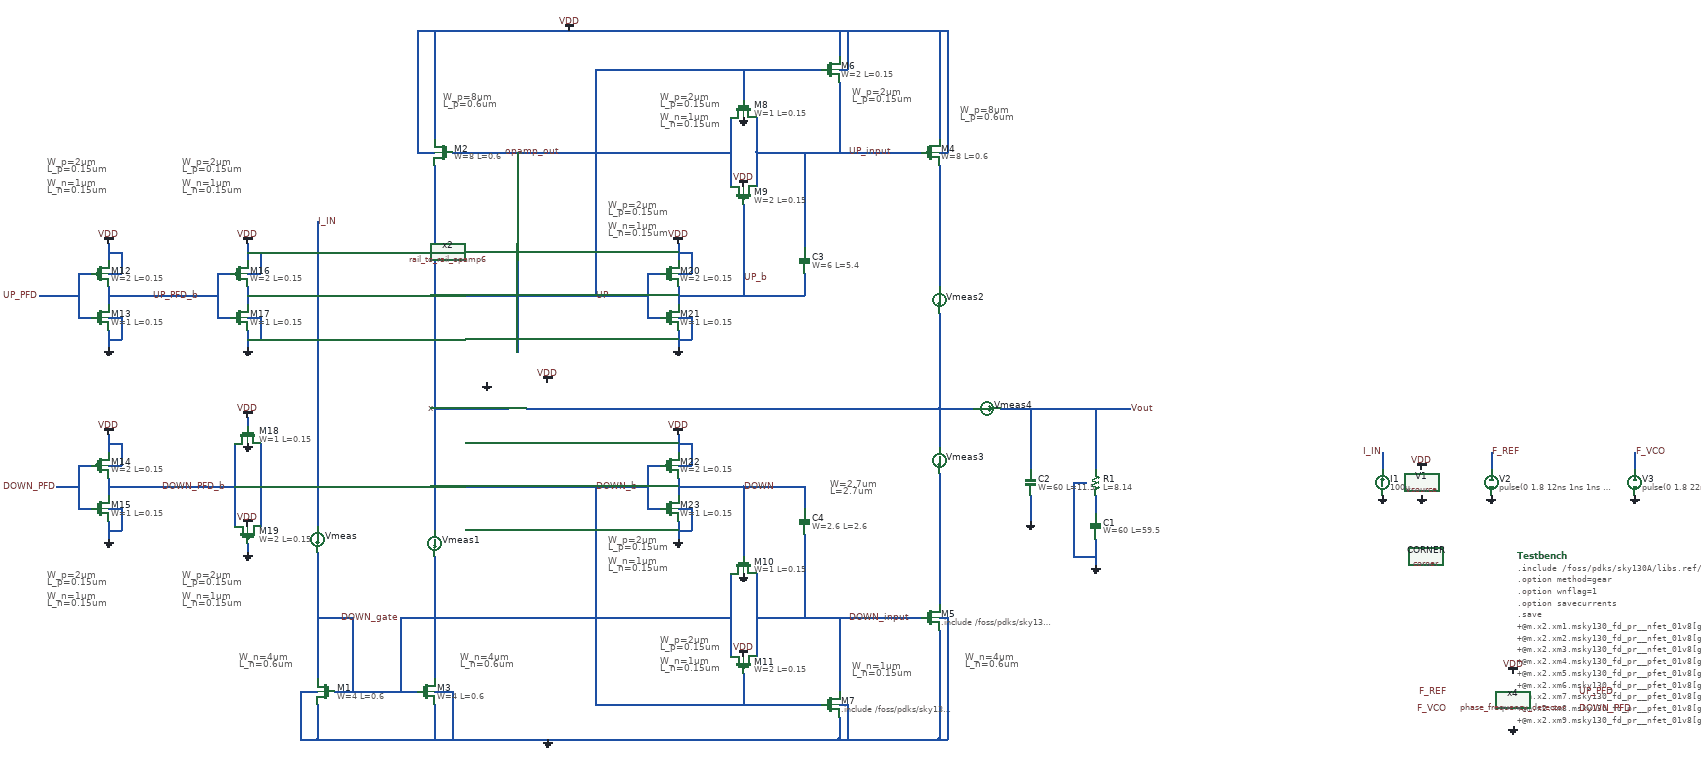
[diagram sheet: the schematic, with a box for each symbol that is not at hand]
v {xschem version=3.4.5 file_version=1.2
}
G {}
K {}
V {}
S {}
E {}
B 2 1320 -2590 2360 -2110 {flags=graph
y1=-0.00011
y2=0.00015
ypos1=0
ypos2=2
divy=5
subdivy=1
unity=1
x1=0
x2=5e-07
divx=5
subdivx=1
xlabmag=1.0
ylabmag=1.0


dataset=0
unitx=1
logx=0
logy=0








linewidth_mult=4
color=6
node="\\"i(@m.xm4.msky130_fd_pr__pfet_01v8[id]) i(@m.xm5.msky130_fd_pr__nfet_01v8[id]) - \\""}
B 2 4200 -3800 5560 -3140 {flags=graph
y1=0
y2=1.8
ypos1=0
ypos2=2
divy=5
subdivy=1
unity=1
x1=0
x2=5e-07
divx=5
subdivx=1
xlabmag=1.0
ylabmag=1.0


dataset=0
unitx=1
logx=0
logy=0








linewidth_mult=3







autoload=0
sim_type=tran
color="6 7"
node="f_ref
f_vco"}
B 2 4200 -2410 5580 -1730 {flags=graph
y1=-0.02
y2=1.9
ypos1=0
ypos2=2
divy=5
subdivy=1
unity=1
x1=0
x2=5e-07
divx=5
subdivx=1
xlabmag=1.0
ylabmag=1.0


dataset=0
unitx=1
logx=0
logy=0








linewidth_mult=5





color="6 5"
node="up_pfd_b
down_pfd_b"}
B 2 4200 -3120 5580 -2420 {flags=graph
y1=-0.038
y2=1.9
ypos1=0
ypos2=2
divy=5
subdivy=1
unity=1
x1=0
x2=5e-07
divx=5
subdivx=1
xlabmag=1.0
ylabmag=1.0


dataset=0
unitx=1
logx=0
logy=0








linewidth_mult=5

color="6 5"
node="up_pfd
down_pfd"}
B 2 2440 -1870 3800 -1200 {flags=graph
y1=0.12
y2=1.8
ypos1=0
ypos2=2
divy=5
subdivy=1
unity=1
x1=0
x2=5e-07
divx=5
subdivx=1
xlabmag=1.0
ylabmag=1.0


dataset=0
unitx=1
logx=0
logy=0








linewidth_mult=4



color="19 7 6"
node="vout
x
opamp_out"}
B 2 420 -3110 1180 -2770 {flags=graph
y1=-0.12
y2=1.9
ypos1=0
ypos2=2
divy=5
subdivy=1
unity=1
x1=0
x2=5e-07
divx=5
subdivx=1
xlabmag=1.0
ylabmag=1.0


dataset=0
unitx=1
logx=0
logy=0








linewidth_mult=3



color="18 6 11 5 12 17"
node="opamp_out
up_input


down_gate
down_input


x


vout"}
B 2 1320 -3100 2360 -2610 {flags=graph
y1=-0.00012
y2=0.00029
ypos1=0
ypos2=2
divy=5
subdivy=1
unity=1
x1=0
x2=5e-07
divx=5
subdivx=1
xlabmag=1.0
ylabmag=1.0


dataset=0
unitx=1
logx=0
logy=0








linewidth_mult=4




color="6 7"
node="i(vmeas2)
i(vmeas3)"}
B 2 4200 -1710 5580 -1030 {flags=graph
y1=-0.013
y2=1.9
ypos1=0
ypos2=2
divy=5
subdivy=1
unity=1
x1=0
x2=5e-07
divx=5
subdivx=1
xlabmag=1.0
ylabmag=1.0


dataset=0
unitx=1
logx=0
logy=0








linewidth_mult=5





color="6 5"
node="up
down_b"}
B 2 4200 -1010 5580 -330 {flags=graph
y1=-0.04
y2=1.9
ypos1=0
ypos2=2
divy=5
subdivy=1
unity=1
x1=0
x2=5e-07
divx=5
subdivx=1
xlabmag=1.0
ylabmag=1.0


dataset=0
unitx=1
logx=0
logy=0








linewidth_mult=5





color="6 5"
node="up_b
down"}
B 2 260 -2590 1300 -2110 {flags=graph
y1=-0.00014
y2=0.00018
ypos1=0
ypos2=2
divy=5
subdivy=1
unity=1
x1=0
x2=5e-07
divx=5
subdivx=1
xlabmag=1.0
ylabmag=1.0


dataset=0
unitx=1
logx=0
logy=0








linewidth_mult=4

color="6 7 18"
node="i(vmeas1)
i(vmeas2)
i(vmeas4)"}
B 2 2440 -2570 3800 -1900 {flags=graph
y1=0.89
y2=1.8
ypos1=0
ypos2=2
divy=5
subdivy=1
unity=1
x1=0
x2=5e-07
divx=5
subdivx=1
xlabmag=1.0
ylabmag=1.0


dataset=0
unitx=1
logx=0
logy=0








linewidth_mult=4



color=6
node=vout}
B 2 2440 -3270 3800 -2600 {flags=graph
y1=8.8
y2=16
ypos1=0
ypos2=2
divy=5
subdivy=1
unity=1
x1=0
x2=5e-07
divx=5
subdivx=1
xlabmag=1.0
ylabmag=1.0


dataset=0
unitx=1
logx=0
logy=0








linewidth_mult=4



color="6 5"
node="\\"@m.x2.xm11.msky130_fd_pr__pfet_01v8[gm] i(@m.x2.xm11.msky130_fd_pr__pfet_01v8[id]) /\\"


\\"@m.x2.xm12.msky130_fd_pr__nfet_01v8[gm] i(@m.x2.xm12.msky130_fd_pr__nfet_01v8[id]) /\\""}
B 2 2440 -3980 3800 -3310 {flags=graph
y1=8.1e-06
y2=1.4e-05
ypos1=0
ypos2=2
divy=5
subdivy=1
unity=1
x1=0
x2=5e-07
divx=5
subdivx=1
xlabmag=1.0
ylabmag=1.0


dataset=0
unitx=1
logx=0
logy=0








linewidth_mult=4





color="6 7"
node="i(@m.x2.xm1.msky130_fd_pr__nfet_01v8[id])
i(@m.x2.xm6.msky130_fd_pr__pfet_01v8[id])"}
B 2 1040 -3980 2400 -3310 {flags=graph
y1=6.4e-05
y2=0.00051
ypos1=0
ypos2=2
divy=5
subdivy=1
unity=1
x1=0
x2=5e-07
divx=5
subdivx=1
xlabmag=1.0
ylabmag=1.0


dataset=0
unitx=1
logx=0
logy=0








linewidth_mult=4



color="6 7"
node="@m.x2.xm11.msky130_fd_pr__pfet_01v8[gm]


@m.x2.xm12.msky130_fd_pr__nfet_01v8[gm]"}
B 2 -380 -3980 980 -3310 {flags=graph
y1=1.3e-05
y2=1.5e-05
ypos1=0
ypos2=2
divy=5
subdivy=1
unity=1
x1=0
x2=5e-07
divx=5
subdivx=1
xlabmag=1.0
ylabmag=1.0


dataset=0
unitx=1
logx=0
logy=0








linewidth_mult=4




color=6
node=i(v.x2.vmeas)}
T {W_p=2um
L_p=0.15um

W_n=1um
L_n=0.15um} 210 -1680 0 0 0.4 0.4 {}
T {W_p=2um
L_p=0.15um

W_n=1um
L_n=0.15um} 210 -730 0 0 0.4 0.4 {}
T {W_p=2um
L_p=0.15um

W_n=1um
L_n=0.15um} 520 -1680 0 0 0.4 0.4 {}
T {W_p=2um
L_p=0.15um

W_n=1um
L_n=0.15um} 520 -730 0 0 0.4 0.4 {}
T {W_p=2um
L_p=0.15um

W_n=1um
L_n=0.15um} 1500 -1580 0 0 0.4 0.4 {}
T {W_p=2um
L_p=0.15um

W_n=1um
L_n=0.15um} 1500 -810 0 0 0.4 0.4 {}
T {W_n=4um
L_n=0.6um} 650 -540 0 0 0.4 0.4 {}
T {W_n=4um
L_n=0.6um} 1160 -540 0 0 0.4 0.4 {}
T {W_p=2um
L_p=0.15um

W_n=1um
L_n=0.15um} 1620 -580 0 0 0.4 0.4 {}
T {W_p=2um
L_p=0.15um

W_n=1um
L_n=0.15um} 1620 -1830 0 0 0.4 0.4 {}
T {W_p=8um
L_p=0.6um} 1120 -1830 0 0 0.4 0.4 {}
T {W_p=8um
L_p=0.6um} 2310 -1800 0 0 0.4 0.4 {}
T {W_n=4um
L_n=0.6um} 2320 -540 0 0 0.4 0.4 {}
T {W_n=1um
L_n=0.15um} 2060 -520 0 0 0.4 0.4 {}
T {W_p=2um
L_p=0.15um} 2060 -1840 0 0 0.4 0.4 {}
T {W=2.7um
L=2.7um} 2010 -940 0 0 0.4 0.4 {}
N 2620 -900 2620 -850 {
lab=#net1}
N 2620 -1100 2620 -960 {
lab=Vout}
N 2620 -800 2620 -740 {
lab=GND}
N 2570 -930 2600 -930 {
lab=GND}
N 2570 -930 2570 -760 {
lab=GND}
N 2570 -760 2620 -760 {
lab=GND}
N 2470 -1100 2470 -960 {
lab=Vout}
N 2470 -900 2470 -840 {
lab=GND}
N 3530 -1000 3530 -960 {
lab=F_REF}
N 3860 -1000 3860 -960 {
lab=F_VCO}
N 2400 -1100 2700 -1100 {
lab=Vout}
N 3280 -1000 3280 -960 {
lab=I_IN}
N 870 -450 1060 -450 {
lab=DOWN_gate}
N 830 -420 830 -340 {
lab=GND}
N 830 -340 1390 -340 {
lab=GND}
N 790 -450 830 -450 {
lab=GND}
N 790 -450 790 -340 {
lab=GND}
N 790 -340 830 -340 {
lab=GND}
N 1100 -450 1140 -450 {
lab=GND}
N 1060 -1690 1100 -1690 {
lab=VDD}
N 1390 -340 1430 -340 {
lab=GND}
N 1100 -1970 1100 -1720 {
lab=VDD}
N 1060 -1970 1060 -1690 {
lab=VDD}
N 2260 -1970 2260 -1720 {
lab=VDD}
N 2030 -1970 2030 -1910 {
lab=VDD}
N 2030 -1880 2050 -1880 {
lab=VDD}
N 2050 -1970 2050 -1880 {
lab=VDD}
N 2280 -1970 2280 -1690 {
lab=VDD}
N 2260 -1690 2280 -1690 {
lab=VDD}
N 2260 -1660 2260 -1380 {
lab=#net2}
N 1430 -340 2030 -340 {
lab=GND}
N 2030 -390 2030 -340 {
lab=GND}
N 2260 -620 2280 -620 {
lab=GND}
N 2260 -340 2280 -340 {
lab=GND}
N 450 -1360 550 -1360 {
lab=UP_PFD_b}
N 490 -920 640 -920 {
lab=DOWN_PFD_b}
N 190 -1360 230 -1360 {
lab=UP_PFD}
N 230 -920 270 -920 {
lab=DOWN_PFD}
N 1100 -1660 1100 -1220 {
lab=x}
N 1100 -1100 1270 -1100 {
lab=x}
N 1310 -1100 2260 -1100 {
lab=#net3}
N 1290 -1690 1290 -1230 {
lab=opamp_out}
N 910 -620 910 -450 {
lab=DOWN_gate}
N 830 -620 910 -620 {
lab=DOWN_gate}
N 1140 -450 1140 -340 {
lab=GND}
N 1100 -420 1100 -340 {
lab=GND}
N 1020 -620 1780 -620 {
lab=DOWN_gate}
N 700 -920 1540 -920 {
lab=DOWN_b}
N 1810 -1570 1810 -1360 {
lab=UP_b}
N 1470 -1880 1990 -1880 {
lab=UP}
N 1470 -1880 1470 -1360 {
lab=UP}
N 2030 -1850 2030 -1690 {
lab=UP_input}
N 1840 -1690 2220 -1690 {
lab=UP_input}
N 1060 -1970 2280 -1970 {
lab=VDD}
N 1750 -920 1810 -920 {
lab=DOWN}
N 1810 -920 1810 -760 {
lab=DOWN}
N 1470 -920 1470 -420 {
lab=DOWN_b}
N 1470 -420 1990 -420 {
lab=DOWN_b}
N 640 -1020 640 -830 {
lab=DOWN_PFD_b}
N 700 -1020 700 -830 {
lab=DOWN_b}
N 670 -1080 670 -1060 {
lab=VDD}
N 670 -790 670 -770 {
lab=GND}
N 350 -940 350 -900 {
lab=DOWN_PFD_b}
N 280 -970 310 -970 {
lab=DOWN_PFD}
N 280 -970 280 -870 {
lab=DOWN_PFD}
N 280 -870 310 -870 {
lab=DOWN_PFD}
N 350 -920 490 -920 {
lab=DOWN_PFD_b}
N 270 -920 280 -920 {
lab=DOWN_PFD}
N 350 -840 350 -800 {
lab=GND}
N 350 -1040 350 -1000 {
lab=VDD}
N 350 -970 380 -970 {
lab=VDD}
N 380 -1020 380 -970 {
lab=VDD}
N 350 -1020 380 -1020 {
lab=VDD}
N 350 -870 380 -870 {
lab=GND}
N 380 -870 380 -820 {
lab=GND}
N 350 -820 380 -820 {
lab=GND}
N 350 -1380 350 -1340 {
lab=UP_PFD_b}
N 280 -1410 310 -1410 {
lab=UP_PFD}
N 280 -1410 280 -1310 {
lab=UP_PFD}
N 280 -1310 310 -1310 {
lab=UP_PFD}
N 350 -1360 450 -1360 {
lab=UP_PFD_b}
N 230 -1360 280 -1360 {
lab=UP_PFD}
N 350 -1280 350 -1240 {
lab=GND}
N 350 -1480 350 -1440 {
lab=VDD}
N 350 -1410 380 -1410 {
lab=VDD}
N 380 -1460 380 -1410 {
lab=VDD}
N 350 -1460 380 -1460 {
lab=VDD}
N 350 -1310 380 -1310 {
lab=GND}
N 380 -1310 380 -1260 {
lab=GND}
N 350 -1260 380 -1260 {
lab=GND}
N 670 -1380 670 -1340 {
lab=UP}
N 600 -1410 630 -1410 {
lab=UP_PFD_b}
N 600 -1410 600 -1310 {
lab=UP_PFD_b}
N 600 -1310 630 -1310 {
lab=UP_PFD_b}
N 550 -1360 600 -1360 {
lab=UP_PFD_b}
N 670 -1280 670 -1240 {
lab=GND}
N 670 -1480 670 -1440 {
lab=VDD}
N 670 -1410 700 -1410 {
lab=VDD}
N 700 -1460 700 -1410 {
lab=VDD}
N 670 -1460 700 -1460 {
lab=VDD}
N 670 -1310 700 -1310 {
lab=GND}
N 700 -1310 700 -1260 {
lab=GND}
N 670 -1260 700 -1260 {
lab=GND}
N 1660 -940 1660 -900 {
lab=DOWN}
N 1590 -970 1620 -970 {
lab=DOWN_b}
N 1590 -970 1590 -870 {
lab=DOWN_b}
N 1590 -870 1620 -870 {
lab=DOWN_b}
N 1540 -920 1590 -920 {
lab=DOWN_b}
N 1660 -840 1660 -800 {
lab=GND}
N 1660 -1040 1660 -1000 {
lab=VDD}
N 1660 -970 1690 -970 {
lab=VDD}
N 1690 -1020 1690 -970 {
lab=VDD}
N 1660 -1020 1690 -1020 {
lab=VDD}
N 1660 -870 1690 -870 {
lab=GND}
N 1690 -870 1690 -820 {
lab=GND}
N 1660 -820 1690 -820 {
lab=GND}
N 1660 -920 1750 -920 {
lab=DOWN}
N 1660 -1380 1660 -1340 {
lab=UP_b}
N 1590 -1410 1620 -1410 {
lab=UP}
N 1590 -1410 1590 -1310 {
lab=UP}
N 1590 -1310 1620 -1310 {
lab=UP}
N 1470 -1360 1590 -1360 {
lab=UP}
N 1660 -1280 1660 -1240 {
lab=GND}
N 1660 -1480 1660 -1440 {
lab=VDD}
N 1660 -1410 1690 -1410 {
lab=VDD}
N 1690 -1460 1690 -1410 {
lab=VDD}
N 1660 -1460 1690 -1460 {
lab=VDD}
N 1660 -1310 1690 -1310 {
lab=GND}
N 1690 -1310 1690 -1260 {
lab=GND}
N 1660 -1260 1690 -1260 {
lab=GND}
N 1660 -1360 1750 -1360 {
lab=UP_b}
N 1750 -1360 1810 -1360 {
lab=UP_b}
N 670 -1360 1470 -1360 {
lab=UP}
N 1100 -1220 1100 -1160 {
lab=x}
N 830 -1530 830 -830 {
lab=I_IN}
N 1100 -1160 1100 -820 {
lab=x}
N 1100 -740 1100 -480 {
lab=#net4}
N 830 -770 830 -760 {
lab=DOWN_gate}
N 830 -660 830 -480 {
lab=DOWN_gate}
N 1100 -760 1100 -740 {
lab=#net4}
N 830 -760 830 -660 {
lab=DOWN_gate}
N 1840 -1770 1840 -1690 {
lab=UP_input}
N 1780 -1770 1780 -1610 {
lab=opamp_out}
N 1840 -1690 1840 -1610 {
lab=UP_input}
N 1140 -1690 1780 -1690 {
lab=opamp_out}
N 2030 -340 2260 -340 {
lab=GND}
N 1840 -720 1840 -530 {
lab=DOWN_input}
N 1780 -720 1780 -530 {
lab=DOWN_gate}
N 1840 -620 2220 -620 {
lab=DOWN_input}
N 2260 -590 2260 -340 {
lab=GND}
N 2280 -620 2280 -340 {
lab=GND}
N 1020 -620 1020 -450 {
lab=DOWN_gate}
N 2030 -620 2030 -450 {
lab=DOWN_input}
N 2030 -420 2050 -420 {
lab=GND}
N 2050 -420 2050 -340 {
lab=GND}
N 1810 -1880 1810 -1810 {
lab=UP}
N 2260 -950 2260 -650 {
lab=#net5}
N 2260 -1100 2260 -1010 {
lab=#net3}
N 2260 -1320 2260 -1100 {
lab=#net3}
N 1810 -1360 1950 -1360 {
lab=UP_b}
N 1950 -1410 1950 -1360 {
lab=UP_b}
N 1950 -1690 1950 -1470 {
lab=UP_input}
N 1950 -920 1950 -870 {
lab=DOWN}
N 1950 -810 1950 -620 {
lab=DOWN_input}
N 1810 -920 1950 -920 {
lab=DOWN}
N 2260 -1100 2340 -1100 {
lab=#net3}
N 1810 -490 1810 -420 {
lab=DOWN_b}
C {sky130_fd_pr/corner.sym} 3380 -760 0 0 {name=CORNER only_toplevel=false corner=tt
value="

.include /foss/pdks/sky130A/libs.ref/sky130_fd_sc_hd/spice/sky130_fd_sc_hd.spice

.option method=gear
.option wnflag=1

* V_out initial voltage value for the F_VCO delay of 2ns  (leading)
* .ic v(vout) = 1.8

* V_out initial voltage value for the F_VCO delay of 12ns (lock condition)
.ic v(vout) = 0.83

* V_out initial voltage value for the F_VCO delay of 22ns (lagging)
* .ic v(vout) = 0

.control
  save v(f_ref) save v(f_vco) save v(i_in) save v(up_pfd) v(down_pfd) v(up_pfd_b) v(down_pfd_b) v(up) v(up_b) v(down) v(down_b) v(x) v(opamp_out) v(up_input) v(down_input) v(down_gate) v(vout)

  * timestep for exact simulation results
  * tran 5ps 0.5us

  * timestep for faster simulation results
  tran 50ps 0.5us

  remzerovec
  write pfd_charge_pump_10.raw
  set appendwrite

.endc

"


v(vout)="0.0

.control
  save all

  * timestep for exact simulation results
  tran 5ps 0.5us

  * timestep for faster simulation results
  * tran 50ps 0.5us

  remzerovec
  write pfd_chargA}
C {devices/code.sym} 3590 -761.25 0 0 {name=Testbench only_toplevel=false value="

.include /foss/pdks/sky130A/libs.ref/sky130_fd_sc_hd/spice/sky130_fd_sc_hd.spice

.option method=gear
.option wnflag=1
.option savecurrents

.save
+@m.x2.xm1.msky130_fd_pr__nfet_01v8[gm]
+@m.x2.xm2.msky130_fd_pr__nfet_01v8[gm]
+@m.x2.xm3.msky130_fd_pr__nfet_01v8[gm]
+@m.x2.xm4.msky130_fd_pr__pfet_01v8[gm]
+@m.x2.xm5.msky130_fd_pr__pfet_01v8[gm]
+@m.x2.xm6.msky130_fd_pr__pfet_01v8[gm]
+@m.x2.xm7.msky130_fd_pr__pfet_01v8[gm]
+@m.x2.xm8.msky130_fd_pr__pfet_01v8[gm]
+@m.x2.xm9.msky130_fd_pr__nfet_01v8[gm]
+@m.x2.xm10.msky130_fd_pr__nfet_01v8[gm]
+@m.x2.xm11.msky130_fd_pr__pfet_01v8[gm]
+@m.x2.xm12.msky130_fd_pr__nfet_01v8[gm]
+@m.x2.xm13.msky130_fd_pr__pfet_01v8[gm]
+@m.x2.xm15.msky130_fd_pr__nfet_01v8[gm]

* V_out initial voltage value for the F_VCO delay of 2ns  (leading)
* .ic v(vout) = 1.8

* V_out initial voltage value for the F_VCO delay of 12ns (lock condition)
* .ic v(vout) = 0.83

* V_out initial voltage value for the F_VCO delay of 22ns (lagging)
.ic v(vout) = 0.0

.control
  * save v(f_ref) save v(f_vco) save v(i_in) save v(up_pfd) v(down_pfd) v(up_pfd_b) v(down_pfd_b) v(up) v(up_b) v(down) v(down_b) v(x) v(opamp_out) v(up_input) v(down_input) v(down_gate) v(vout)
  save all

  * timestep for exact simulation results
  * tran 5ps 0.5us

  * timestep for faster simulation results
  tran 50ps 0.5us

  remzerovec
  write pfd_charge_pump_10.raw
  * write pfd_charge_pump_10_2.raw
  * write pfd_charge_pump_10_3.raw
  * write pfd_charge_pump_10_4.raw
  * write pfd_charge_pump_10_5.raw
  * write pfd_charge_pump_10_6.raw
  * write pfd_charge_pump_10_7.raw
  * write pfd_charge_pump_10_8.raw
  * write pfd_charge_pump_10_9.raw
  * write pfd_charge_pump_10_10.raw
  set appendwrite

.endc

"
}
C {devices/vsource.sym} 3370 -930 0 0 {name=V1 value=1.8 savecurrent=false}
C {devices/gnd.sym} 3370 -900 0 0 {name=l2 lab=GND}
C {devices/vdd.sym} 3370 -960 0 1 {name=l3 lab=VDD}
C {devices/lab_wire.sym} 2700 -1100 0 1 {name=p9 sig_type=std_logic lab=Vout}
C {sky130_fd_pr/cap_mim_m3_1.sym} 2470 -930 0 0 {name=C2 model=cap_mim_m3_1 W=60 L=11.5 MF=1 spiceprefix=X}
C {sky130_fd_pr/cap_mim_m3_1.sym} 2620 -830 0 0 {name=C1 model=cap_mim_m3_1 W=60 L=59.5 MF=1 spiceprefix=X}
C {devices/gnd.sym} 2620 -740 0 0 {name=l4 lab=GND
value="

.include /foss/pdks/sky130A/libs.ref/sky130_fd_sc_hd/spice/sky130_fd_sc_hd.spice

.option method=gear
.option wnflag=1

* V_out initial voltage value for the F_VCO delay of 2ns  (leading)
* .ic v(vout) = 1.8

* V_out initial voltage value for the F_VCO delay of 12ns (lock condition)
.ic v(vout) = 0.83

* V_out initial voltage value for the F_VCO delay of 22ns (lagging)
* .ic v(vout) = 0

.control
  save v(f_ref) save v(f_vco) save v(i_in) save v(up_pfd) v(down_pfd) v(up_pfd_b) v(down_pfd_b) v(up) v(up_b) v(down) v(down_b) v(x) v(opamp_out) v(up_input) v(down_input) v(down_gate) v(vout)

  * timestep for exact simulation results
  * tran 5ps 0.5us

  * timestep for faster simulation results
  tran 50ps 0.5us

  remzerovec
  write pfd_charge_pump_10.raw
  set appendwrite

.endc

"}
C {devices/gnd.sym} 2470 -840 0 0 {name=l9 lab=GND
W=60}
C {devices/vsource.sym} 3530 -930 0 0 {name=V2 value=pulse"(0 1.8 12ns 1ns 1ns 24ns 50ns)" savecurrent=false
* }
C {devices/gnd.sym} 3530 -900 0 0 {name=l10 lab=GND}
C {devices/lab_pin.sym} 3530 -1000 0 1 {name=p11 sig_type=std_logic lab=F_REF}
C {devices/vsource.sym} 3860 -930 0 0 {name=V3 value="pulse(0 1.8 22ns 1ns 1ns 24ns 50ns)" savecurrent=false
* "sin(0.9 0.9 20.1MEG)" 1 AC 1}
C {devices/gnd.sym} 3860 -900 0 0 {name=l15 lab=GND}
C {devices/lab_pin.sym} 3860 -1000 0 1 {name=p12 sig_type=std_logic lab=F_VCO}
C {/foss/designs/my_design/projects/pll/pfd/xschem_ngspice/phase_frequency_detector.sym} 3580 -430 0 0 {name=x4
value="

.include /foss/pdks/sky130A/libs.ref/sky130_fd_sc_hd/spice/sky130_fd_sc_hd.spice

.option method=gear
.option wnflag=1

* V_out initial voltage value for the F_VCO delay of 2ns  (leading)
* .ic v(vout) = 1.8

* V_out initial voltage value for the F_VCO delay of 12ns (lock condition)
.ic v(vout) = 0.83

* V_out initial voltage value for the F_VCO delay of 22ns (lagging)
* .ic v(vout) = 0

.control
  save v(f_ref) save v(f_vco) save v(i_in) save v(up_pfd) v(down_pfd) v(up_pfd_b) v(down_pfd_b) v(up) v(up_b) v(down) v(down_b) v(x) v(opamp_out) v(up_input) v(down_input) v(down_gate) v(vout)

  * timestep for exact simulation results
  * tran 5ps 0.5us

  * timestep for faster simulation results
  tran 50ps 0.5us

  remzerovec
  write pfd_charge_pump_10.raw
  set appendwrite

.endc

"


v(vout)="0.0

.control
  save all

  * timestep for exact simulation results
  tran 5ps 0.5us

  * timestep for faster simulation results
  * tran 50ps 0.5us

  remzerovec
  write pfd_charge_pump_10.raw
  set appendwrite

.!}
C {devices/lab_pin.sym} 3430 -450 0 0 {name=p19 lab=F_REF
value="

.include /foss/pdks/sky130A/libs.ref/sky130_fd_sc_hd/spice/sky130_fd_sc_hd.spice

.option method=gear
.option wnflag=1

* V_out initial voltage value for the F_VCO delay of 2ns  (leading)
* .ic v(vout) = 1.8

* V_out initial voltage value for the F_VCO delay of 12ns (lock condition)
.ic v(vout) = 0.83

* V_out initial voltage value for the F_VCO delay of 22ns (lagging)
* .ic v(vout) = 0

.control
  save v(f_ref) save v(f_vco) save v(i_in) save v(up_pfd) v(down_pfd) v(up_pfd_b) v(down_pfd_b) v(up) v(up_b) v(down) v(down_b) v(x) v(opamp_out) v(up_input) v(down_input) v(down_gate) v(vout)

  * timestep for exact simulation results
  * tran 5ps 0.5us

  * timestep for faster simulation results
  tran 50ps 0.5us

  remzerovec
  write pfd_charge_pump_10.raw
  set appendwrite

.endc

"


v(vout)="0.0

.control
  save all

  * timestep for exact simulation results
  tran 5ps 0.5us

  * timestep for faster simulation results
  * tran 50ps 0.5us

  remzerovec
  write pfd_charge_pump_10.raw
  set appA}
C {devices/lab_pin.sym} 3430 -410 0 0 {name=p20 lab=F_VCO
value="

.include /foss/pdks/sky130A/libs.ref/sky130_fd_sc_hd/spice/sky130_fd_sc_hd.spice

.option method=gear
.option wnflag=1

* V_out initial voltage value for the F_VCO delay of 2ns  (leading)
* .ic v(vout) = 1.8

* V_out initial voltage value for the F_VCO delay of 12ns (lock condition)
.ic v(vout) = 0.83

* V_out initial voltage value for the F_VCO delay of 22ns (lagging)
* .ic v(vout) = 0

.control
  save v(f_ref) save v(f_vco) save v(i_in) save v(up_pfd) v(down_pfd) v(up_pfd_b) v(down_pfd_b) v(up) v(up_b) v(down) v(down_b) v(x) v(opamp_out) v(up_input) v(down_input) v(down_gate) v(vout)

  * timestep for exact simulation results
  * tran 5ps 0.5us

  * timestep for faster simulation results
  tran 50ps 0.5us

  remzerovec
  write pfd_charge_pump_10.raw
  set appendwrite

.endc

"


v(vout)="0.0

.control
  save all

  * timestep for exact simulation results
  tran 5ps 0.5us

  * timestep for faster simulation results
  * tran 50ps 0.5us

  remzerovec
  write pfd_charge_pump_10.raw
  set appA}
C {devices/lab_wire.sym} 3730 -450 0 1 {name=p22 sig_type=std_logic lab=UP_PFD}
C {devices/lab_wire.sym} 3730 -410 2 0 {name=p23 sig_type=std_logic lab=DOWN_PFD}
C {devices/vdd.sym} 3580 -490 0 1 {name=l1 lab=VDD
value="

.include /foss/pdks/sky130A/libs.ref/sky130_fd_sc_hd/spice/sky130_fd_sc_hd.spice

.option method=gear
.option wnflag=1

* V_out initial voltage value for the F_VCO delay of 2ns  (leading)
* .ic v(vout) = 1.8

* V_out initial voltage value for the F_VCO delay of 12ns (lock condition)
.ic v(vout) = 0.83

* V_out initial voltage value for the F_VCO delay of 22ns (lagging)
* .ic v(vout) = 0

.control
  save v(f_ref) save v(f_vco) save v(i_in) save v(up_pfd) v(down_pfd) v(up_pfd_b) v(down_pfd_b) v(up) v(up_b) v(down) v(down_b) v(x) v(opamp_out) v(up_input) v(down_input) v(down_gate) v(vout)

  * timestep for exact simulation results
  * tran 5ps 0.5us

  * timestep for faster simulation results
  tran 50ps 0.5us

  remzerovec
  write pfd_charge_pump_10.raw
  set appendwrite

.endc

"


v(vout)="0.0

.control
  save all

  * timestep for exact simulation results
  tran 5ps 0.5us

  * timestep for faster simulation results
  * tran 50ps 0.5us

  remzerovec
  write pfd_charge_pump_10.raw
  set appendA}
C {devices/gnd.sym} 3580 -370 0 0 {name=l8 lab=GND
value="

.include /foss/pdks/sky130A/libs.ref/sky130_fd_sc_hd/spice/sky130_fd_sc_hd.spice

.option method=gear
.option wnflag=1

* V_out initial voltage value for the F_VCO delay of 2ns  (leading)
* .ic v(vout) = 1.8

* V_out initial voltage value for the F_VCO delay of 12ns (lock condition)
.ic v(vout) = 0.83

* V_out initial voltage value for the F_VCO delay of 22ns (lagging)
* .ic v(vout) = 0

.control
  save v(f_ref) save v(f_vco) save v(i_in) save v(up_pfd) v(down_pfd) v(up_pfd_b) v(down_pfd_b) v(up) v(up_b) v(down) v(down_b) v(x) v(opamp_out) v(up_input) v(down_input) v(down_gate) v(vout)

  * timestep for exact simulation results
  * tran 5ps 0.5us

  * timestep for faster simulation results
  tran 50ps 0.5us

  remzerovec
  write pfd_charge_pump_10.raw
  set appendwrite

.endc

"}
C {sky130_fd_pr/res_xhigh_po_0p35.sym} 2620 -930 0 0 {name=R1
L=8.14
model=res_xhigh_po_0p35
spiceprefix=X
mult=1}
C {devices/isource.sym} 3280 -930 2 0 {name=I1 value=100u}
C {devices/gnd.sym} 3280 -900 0 0 {name=l26 lab=GND}
C {devices/lab_pin.sym} 3280 -1000 2 1 {name=p3 sig_type=std_logic lab=I_IN}
C {devices/ammeter.sym} 2260 -980 0 0 {name=Vmeas3 savecurrent=true spice_ignore=0}
C {sky130_fd_pr/nfet_01v8.sym} 850 -450 0 1 {name=M1
L=0.6
W=4
nf=1 
mult=1
ad="'int((nf+1)/2) * W/nf * 0.29'" 
pd="'2*int((nf+1)/2) * (W/nf + 0.29)'"
as="'int((nf+2)/2) * W/nf * 0.29'" 
ps="'2*int((nf+2)/2) * (W/nf + 0.29)'"
nrd="'0.29 / W'" nrs="'0.29 / W'"
sa=0 sb=0 sd=0
model=nfet_01v8
spiceprefix=X
}
C {sky130_fd_pr/nfet_01v8.sym} 1080 -450 0 0 {name=M3
L=0.6
W=4
nf=1 
mult=1
ad="'int((nf+1)/2) * W/nf * 0.29'" 
pd="'2*int((nf+1)/2) * (W/nf + 0.29)'"
as="'int((nf+2)/2) * W/nf * 0.29'" 
ps="'2*int((nf+2)/2) * (W/nf + 0.29)'"
nrd="'0.29 / W'" nrs="'0.29 / W'"
sa=0 sb=0 sd=0
model=nfet_01v8
spiceprefix=X
}
C {sky130_fd_pr/pfet_01v8.sym} 1120 -1690 2 0 {name=M2
L=0.6
W=8
nf=8
mult=1
ad="'int((nf+1)/2) * W/nf * 0.29'" 
pd="'2*int((nf+1)/2) * (W/nf + 0.29)'"
as="'int((nf+2)/2) * W/nf * 0.29'" 
ps="'2*int((nf+2)/2) * (W/nf + 0.29)'"
nrd="'0.29 / W'" nrs="'0.29 / W'"
sa=0 sb=0 sd=0
model=pfet_01v8
spiceprefix=X
}
C {devices/vdd.sym} 1410 -1970 0 0 {name=l13 lab=VDD}
C {devices/gnd.sym} 1360 -340 0 0 {name=l14 lab=GND}
C {devices/lab_wire.sym} 1100 -1100 0 0 {name=p2 sig_type=std_logic lab=x}
C {sky130_fd_pr/pfet_01v8.sym} 1810 -1590 1 1 {name=M9
L=0.15
W=2
nf=2
mult=1
ad="'int((nf+1)/2) * W/nf * 0.29'" 
pd="'2*int((nf+1)/2) * (W/nf + 0.29)'"
as="'int((nf+2)/2) * W/nf * 0.29'" 
ps="'2*int((nf+2)/2) * (W/nf + 0.29)'"
nrd="'0.29 / W'" nrs="'0.29 / W'"
sa=0 sb=0 sd=0
model=pfet_01v8
spiceprefix=X
}
C {sky130_fd_pr/pfet_01v8.sym} 2010 -1880 0 0 {name=M6
L=0.15
W=2
nf=2
mult=1
ad="'int((nf+1)/2) * W/nf * 0.29'" 
pd="'2*int((nf+1)/2) * (W/nf + 0.29)'"
as="'int((nf+2)/2) * W/nf * 0.29'" 
ps="'2*int((nf+2)/2) * (W/nf + 0.29)'"
nrd="'0.29 / W'" nrs="'0.29 / W'"
sa=0 sb=0 sd=0
model=pfet_01v8
spiceprefix=X
}
C {sky130_fd_pr/pfet_01v8.sym} 2240 -1690 0 0 {name=M4
L=0.6
W=8
nf=8
mult=1
ad="'int((nf+1)/2) * W/nf * 0.29'" 
pd="'2*int((nf+1)/2) * (W/nf + 0.29)'"
as="'int((nf+2)/2) * W/nf * 0.29'" 
ps="'2*int((nf+2)/2) * (W/nf + 0.29)'"
nrd="'0.29 / W'" nrs="'0.29 / W'"
sa=0 sb=0 sd=0
model=pfet_01v8
spiceprefix=X
}
C {devices/lab_wire.sym} 1470 -1360 2 0 {name=p4 sig_type=std_logic lab=UP}
C {devices/lab_wire.sym} 1810 -1400 0 1 {name=p5 sig_type=std_logic lab=UP_b}
C {sky130_fd_pr/nfet_01v8.sym} 1810 -740 1 0 {name=M10
L=0.15
W=1
nf=1 
mult=1
ad="'int((nf+1)/2) * W/nf * 0.29'" 
pd="'2*int((nf+1)/2) * (W/nf + 0.29)'"
as="'int((nf+2)/2) * W/nf * 0.29'" 
ps="'2*int((nf+2)/2) * (W/nf + 0.29)'"
nrd="'0.29 / W'" nrs="'0.29 / W'"
sa=0 sb=0 sd=0
model=nfet_01v8
spiceprefix=X
}
C {sky130_fd_pr/nfet_01v8.sym} 2010 -420 0 0 {name=M7
L=0.15
W=1
nf=1 
mult=1
ad="'int((nf+1)/2) * W/nf * 0.29'" 
pd="'2*int((nf+1)/2) * (W/nf + 0.29)'"
as="'int((nf+2)/2) * W/nf * 0.29'" 
ps="'2*int((nf+2)/2) * (W/nf + 0.29)'"
nrd="'0.29 / W'" nrs="'0.29 / W'"
sa=0 sb=0 sd=0
model=nfet_01v8
spiceprefix=X
value="

.include /foss/pdks/sky130A/libs.ref/sky130_fd_sc_hd/spice/sky130_fd_sc_hd.spice

.option method=gear
.option wnflag=1

* V_out initial voltage value for the F_VCO delay of 2ns  (leading)
* .ic v(vout) = 1.8

* V_out initial voltage value for the F_VCO delay of 12ns (lock condition)
.ic v(vout) = 0.83

* V_out initial voltage value for the F_VCO delay of 22ns (lagging)
* .ic v(vout) = 0

.control
  save v(f_ref) save v(f_vco) save v(i_in) save v(up_pfd) v(down_pfd) v(up_pfd_b) v(down_pfd_b) v(up) v(up_b) v(down) v(down_b) v(x) v(opamp_out) v(up_input) v(down_input) v(down_gate) v(vout)

  * timestep for exact simulation results
  * tran 5ps 0.5us

  * timestep for faster simulation results
  tran 50ps 0.5us

  remzerovec
  write pfd_charge_pump_10.raw
  set appendwrite

.endc

"}
C {devices/lab_wire.sym} 1470 -920 0 1 {name=p6 sig_type=std_logic lab=DOWN_b}
C {sky130_fd_pr/nfet_01v8.sym} 2240 -620 0 0 {name=M5
L=0.6
W=4
nf=1 
mult=1
ad="'int((nf+1)/2) * W/nf * 0.29'" 
pd="'2*int((nf+1)/2) * (W/nf + 0.29)'"
as="'int((nf+2)/2) * W/nf * 0.29'" 
ps="'2*int((nf+2)/2) * (W/nf + 0.29)'"
nrd="'0.29 / W'" nrs="'0.29 / W'"
sa=0 sb=0 sd=0
model=nfet_01v8
spiceprefix=X
value="

.include /foss/pdks/sky130A/libs.ref/sky130_fd_sc_hd/spice/sky130_fd_sc_hd.spice

.option method=gear
.option wnflag=1

* V_out initial voltage value for the F_VCO delay of 2ns  (leading)
* .ic v(vout) = 1.8

* V_out initial voltage value for the F_VCO delay of 12ns (lock condition)
.ic v(vout) = 0.83

* V_out initial voltage value for the F_VCO delay of 22ns (lagging)
* .ic v(vout) = 0

.control
  save v(f_ref) save v(f_vco) save v(i_in) save v(up_pfd) v(down_pfd) v(up_pfd_b) v(down_pfd_b) v(up) v(up_b) v(down) v(down_b) v(x) v(opamp_out) v(up_input) v(down_input) v(down_gate) v(vout)

  * timestep for exact simulation results
  * tran 5ps 0.5us

  * timestep for faster simulation results
  tran 50ps 0.5us

  remzerovec
  write pfd_charge_pump_10.raw
  set appendwrite

.endc

"}
C {devices/lab_wire.sym} 450 -1360 0 1 {name=p15 sig_type=std_logic lab=UP_PFD_b}
C {devices/lab_wire.sym} 2050 -1690 2 0 {name=p13 sig_type=std_logic lab=UP_input}
C {devices/lab_wire.sym} 2050 -620 0 1 {name=p14 sig_type=std_logic lab=DOWN_input
value="

.include /foss/pdks/sky130A/libs.ref/sky130_fd_sc_hd/spice/sky130_fd_sc_hd.spice

.option method=gear
.option wnflag=1

* V_out initial voltage value for the F_VCO delay of 2ns  (leading)
* .ic v(vout) = 1.8

* V_out initial voltage value for the F_VCO delay of 12ns (lock condition)
.ic v(vout) = 0.83

* V_out initial voltage value for the F_VCO delay of 22ns (lagging)
* .ic v(vout) = 0

.control
  save v(f_ref) save v(f_vco) save v(i_in) save v(up_pfd) v(down_pfd) v(up_pfd_b) v(down_pfd_b) v(up) v(up_b) v(down) v(down_b) v(x) v(opamp_out) v(up_input) v(down_input) v(down_gate) v(vout)

  * timestep for exact simulation results
  * tran 5ps 0.5us

  * timestep for faster simulation results
  tran 50ps 0.5us

  remzerovec
  write pfd_charge_pump_10.raw
  set appendwrite

.endc

"}
C {devices/gnd.sym} 1220 -1160 0 1 {name=l7 lab=GND}
C {devices/lab_wire.sym} 1390 -1690 0 0 {name=p17 sig_type=std_logic lab=opamp_out}
C {devices/lab_wire.sym} 190 -1360 0 0 {name=p7 sig_type=std_logic lab=UP_PFD}
C {devices/lab_wire.sym} 230 -920 2 1 {name=p8 sig_type=std_logic lab=DOWN_PFD}
C {/foss/designs/my_design/projects/pll/charge_pump/xschem_ngspice/rail_to_rail_opamp6.sym} 1290 -1160 1 1 {name=x2}
C {devices/vdd.sym} 1360 -1160 0 0 {name=l6 lab=VDD}
C {sky130_fd_pr/pfet_01v8.sym} 670 -810 3 0 {name=M19
L=0.15
W=2
nf=2
mult=1
ad="'int((nf+1)/2) * W/nf * 0.29'" 
pd="'2*int((nf+1)/2) * (W/nf + 0.29)'"
as="'int((nf+2)/2) * W/nf * 0.29'" 
ps="'2*int((nf+2)/2) * (W/nf + 0.29)'"
nrd="'0.29 / W'" nrs="'0.29 / W'"
sa=0 sb=0 sd=0
model=pfet_01v8
spiceprefix=X
}
C {sky130_fd_pr/nfet_01v8.sym} 670 -1040 1 0 {name=M18
L=0.15
W=1
nf=1 
mult=1
ad="'int((nf+1)/2) * W/nf * 0.29'" 
pd="'2*int((nf+1)/2) * (W/nf + 0.29)'"
as="'int((nf+2)/2) * W/nf * 0.29'" 
ps="'2*int((nf+2)/2) * (W/nf + 0.29)'"
nrd="'0.29 / W'" nrs="'0.29 / W'"
sa=0 sb=0 sd=0
model=nfet_01v8
spiceprefix=X
}
C {devices/vdd.sym} 670 -1080 0 0 {name=l11 lab=VDD}
C {devices/gnd.sym} 670 -770 0 0 {name=l12 lab=GND}
C {sky130_fd_pr/pfet_01v8.sym} 330 -970 0 0 {name=M14
L=0.15
W=2
nf=2
mult=1
ad="'int((nf+1)/2) * W/nf * 0.29'" 
pd="'2*int((nf+1)/2) * (W/nf + 0.29)'"
as="'int((nf+2)/2) * W/nf * 0.29'" 
ps="'2*int((nf+2)/2) * (W/nf + 0.29)'"
nrd="'0.29 / W'" nrs="'0.29 / W'"
sa=0 sb=0 sd=0
model=pfet_01v8
spiceprefix=X
}
C {sky130_fd_pr/nfet_01v8.sym} 330 -870 2 1 {name=M15
L=0.15
W=1
nf=1 
mult=1
ad="'int((nf+1)/2) * W/nf * 0.29'" 
pd="'2*int((nf+1)/2) * (W/nf + 0.29)'"
as="'int((nf+2)/2) * W/nf * 0.29'" 
ps="'2*int((nf+2)/2) * (W/nf + 0.29)'"
nrd="'0.29 / W'" nrs="'0.29 / W'"
sa=0 sb=0 sd=0
model=nfet_01v8
spiceprefix=X
}
C {devices/gnd.sym} 350 -800 0 0 {name=l16 lab=GND}
C {devices/vdd.sym} 350 -1040 0 0 {name=l17 lab=VDD}
C {sky130_fd_pr/pfet_01v8.sym} 330 -1410 0 0 {name=M12
L=0.15
W=2
nf=2
mult=1
ad="'int((nf+1)/2) * W/nf * 0.29'" 
pd="'2*int((nf+1)/2) * (W/nf + 0.29)'"
as="'int((nf+2)/2) * W/nf * 0.29'" 
ps="'2*int((nf+2)/2) * (W/nf + 0.29)'"
nrd="'0.29 / W'" nrs="'0.29 / W'"
sa=0 sb=0 sd=0
model=pfet_01v8
spiceprefix=X
}
C {sky130_fd_pr/nfet_01v8.sym} 330 -1310 2 1 {name=M13
L=0.15
W=1
nf=1 
mult=1
ad="'int((nf+1)/2) * W/nf * 0.29'" 
pd="'2*int((nf+1)/2) * (W/nf + 0.29)'"
as="'int((nf+2)/2) * W/nf * 0.29'" 
ps="'2*int((nf+2)/2) * (W/nf + 0.29)'"
nrd="'0.29 / W'" nrs="'0.29 / W'"
sa=0 sb=0 sd=0
model=nfet_01v8
spiceprefix=X
}
C {devices/gnd.sym} 350 -1240 0 0 {name=l18 lab=GND}
C {devices/vdd.sym} 350 -1480 0 0 {name=l19 lab=VDD}
C {sky130_fd_pr/pfet_01v8.sym} 650 -1410 0 0 {name=M16
L=0.15
W=2
nf=2
mult=1
ad="'int((nf+1)/2) * W/nf * 0.29'" 
pd="'2*int((nf+1)/2) * (W/nf + 0.29)'"
as="'int((nf+2)/2) * W/nf * 0.29'" 
ps="'2*int((nf+2)/2) * (W/nf + 0.29)'"
nrd="'0.29 / W'" nrs="'0.29 / W'"
sa=0 sb=0 sd=0
model=pfet_01v8
spiceprefix=X
}
C {sky130_fd_pr/nfet_01v8.sym} 650 -1310 2 1 {name=M17
L=0.15
W=1
nf=1 
mult=1
ad="'int((nf+1)/2) * W/nf * 0.29'" 
pd="'2*int((nf+1)/2) * (W/nf + 0.29)'"
as="'int((nf+2)/2) * W/nf * 0.29'" 
ps="'2*int((nf+2)/2) * (W/nf + 0.29)'"
nrd="'0.29 / W'" nrs="'0.29 / W'"
sa=0 sb=0 sd=0
model=nfet_01v8
spiceprefix=X
}
C {devices/gnd.sym} 670 -1240 0 0 {name=l20 lab=GND}
C {devices/vdd.sym} 670 -1480 0 0 {name=l21 lab=VDD}
C {sky130_fd_pr/pfet_01v8.sym} 1640 -970 0 0 {name=M22
L=0.15
W=2
nf=2
mult=1
ad="'int((nf+1)/2) * W/nf * 0.29'" 
pd="'2*int((nf+1)/2) * (W/nf + 0.29)'"
as="'int((nf+2)/2) * W/nf * 0.29'" 
ps="'2*int((nf+2)/2) * (W/nf + 0.29)'"
nrd="'0.29 / W'" nrs="'0.29 / W'"
sa=0 sb=0 sd=0
model=pfet_01v8
spiceprefix=X
}
C {sky130_fd_pr/nfet_01v8.sym} 1640 -870 2 1 {name=M23
L=0.15
W=1
nf=1 
mult=1
ad="'int((nf+1)/2) * W/nf * 0.29'" 
pd="'2*int((nf+1)/2) * (W/nf + 0.29)'"
as="'int((nf+2)/2) * W/nf * 0.29'" 
ps="'2*int((nf+2)/2) * (W/nf + 0.29)'"
nrd="'0.29 / W'" nrs="'0.29 / W'"
sa=0 sb=0 sd=0
model=nfet_01v8
spiceprefix=X
}
C {devices/gnd.sym} 1660 -800 0 0 {name=l22 lab=GND}
C {devices/vdd.sym} 1660 -1040 0 0 {name=l23 lab=VDD}
C {sky130_fd_pr/pfet_01v8.sym} 1640 -1410 0 0 {name=M20
L=0.15
W=2
nf=2
mult=1
ad="'int((nf+1)/2) * W/nf * 0.29'" 
pd="'2*int((nf+1)/2) * (W/nf + 0.29)'"
as="'int((nf+2)/2) * W/nf * 0.29'" 
ps="'2*int((nf+2)/2) * (W/nf + 0.29)'"
nrd="'0.29 / W'" nrs="'0.29 / W'"
sa=0 sb=0 sd=0
model=pfet_01v8
spiceprefix=X
}
C {sky130_fd_pr/nfet_01v8.sym} 1640 -1310 2 1 {name=M21
L=0.15
W=1
nf=1 
mult=1
ad="'int((nf+1)/2) * W/nf * 0.29'" 
pd="'2*int((nf+1)/2) * (W/nf + 0.29)'"
as="'int((nf+2)/2) * W/nf * 0.29'" 
ps="'2*int((nf+2)/2) * (W/nf + 0.29)'"
nrd="'0.29 / W'" nrs="'0.29 / W'"
sa=0 sb=0 sd=0
model=nfet_01v8
spiceprefix=X
}
C {devices/gnd.sym} 1660 -1240 0 0 {name=l24 lab=GND}
C {devices/vdd.sym} 1660 -1480 0 0 {name=l25 lab=VDD}
C {devices/lab_wire.sym} 830 -1530 0 1 {name=p16 sig_type=std_logic lab=I_IN}
C {devices/ammeter.sym} 830 -800 0 0 {name=Vmeas savecurrent=true spice_ignore=0}
C {devices/ammeter.sym} 1100 -790 0 0 {name=Vmeas1 savecurrent=true spice_ignore=0}
C {devices/lab_wire.sym} 470 -920 2 0 {name=p10 sig_type=std_logic lab=DOWN_PFD_b}
C {devices/lab_wire.sym} 1810 -920 0 1 {name=p21 sig_type=std_logic lab=DOWN}
C {devices/ammeter.sym} 2260 -1350 0 0 {name=Vmeas2 savecurrent=true spice_ignore=0}
C {devices/ammeter.sym} 2370 -1100 3 0 {name=Vmeas4 savecurrent=true spice_ignore=0}
C {sky130_fd_pr/nfet_01v8.sym} 1810 -1790 1 0 {name=M8
L=0.15
W=1
nf=1 
mult=1
ad="'int((nf+1)/2) * W/nf * 0.29'" 
pd="'2*int((nf+1)/2) * (W/nf + 0.29)'"
as="'int((nf+2)/2) * W/nf * 0.29'" 
ps="'2*int((nf+2)/2) * (W/nf + 0.29)'"
nrd="'0.29 / W'" nrs="'0.29 / W'"
sa=0 sb=0 sd=0
model=nfet_01v8
spiceprefix=X
}
C {sky130_fd_pr/pfet_01v8.sym} 1810 -510 1 1 {name=M11
L=0.15
W=2
nf=2
mult=1
ad="'int((nf+1)/2) * W/nf * 0.29'" 
pd="'2*int((nf+1)/2) * (W/nf + 0.29)'"
as="'int((nf+2)/2) * W/nf * 0.29'" 
ps="'2*int((nf+2)/2) * (W/nf + 0.29)'"
nrd="'0.29 / W'" nrs="'0.29 / W'"
sa=0 sb=0 sd=0
model=pfet_01v8
spiceprefix=X
}
C {devices/vdd.sym} 1810 -1610 0 0 {name=l5 lab=VDD}
C {devices/gnd.sym} 1810 -1770 0 0 {name=l27 lab=GND}
C {devices/gnd.sym} 1810 -720 0 0 {name=l28 lab=GND}
C {devices/vdd.sym} 1810 -530 0 0 {name=l29 lab=VDD}
C {sky130_fd_pr/cap_mim_m3_1.sym} 1950 -1440 0 0 {name=C3 model=cap_mim_m3_1 W=6 L=5.4 MF=1 spiceprefix=X}
C {sky130_fd_pr/cap_mim_m3_1.sym} 1950 -840 0 0 {name=C4 model=cap_mim_m3_1 W=2.6 L=2.6 MF=1 spiceprefix=X}
C {devices/gnd.sym} 670 -1020 0 0 {name=l30 lab=GND}
C {devices/vdd.sym} 670 -830 0 0 {name=l31 lab=VDD}
C {devices/lab_wire.sym} 1020 -620 0 0 {name=p18 sig_type=std_logic lab=DOWN_gate}
